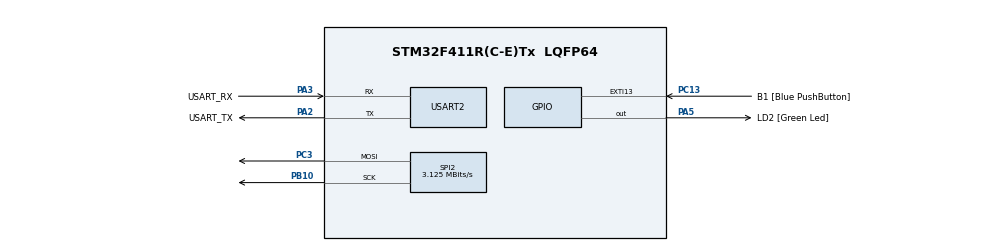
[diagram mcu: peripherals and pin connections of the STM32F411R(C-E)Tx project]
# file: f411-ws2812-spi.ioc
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Dma.Request0=SPI2_TX
Dma.SPI2_TX.0.Direction=DMA_MEMORY_TO_PERIPH
Dma.SPI2_TX.0.FIFOMode=DMA_FIFOMODE_DISABLE
Dma.SPI2_TX.0.Instance=DMA1_Stream4
Dma.SPI2_TX.0.MemDataAlignment=DMA_MDATAALIGN_BYTE
Dma.SPI2_TX.0.MemInc=DMA_MINC_ENABLE
Dma.SPI2_TX.0.Mode=DMA_NORMAL
Dma.SPI2_TX.0.PeriphDataAlignment=DMA_PDATAALIGN_BYTE
Dma.SPI2_TX.0.PeriphInc=DMA_PINC_DISABLE
Dma.SPI2_TX.0.Priority=DMA_PRIORITY_LOW
Mcu.Family=STM32F4
Mcu.Name=STM32F411R(C-E)Tx
Mcu.Package=LQFP64
NVIC.DMA1_Stream4_IRQn=true\:0\:0\:false\:false\:true\:false\:true\:true
NVIC.PriorityGroup=NVIC_PRIORITYGROUP_0
NVIC.SPI2_IRQn=true\:0\:0\:false\:false\:true\:true\:true\:true
PA13.GPIO_Label=TMS
PA13.Mode=Serial_Wire
PA13.Signal=SYS_JTMS-SWDIO
PA14.GPIO_Label=TCK
PA14.Mode=Serial_Wire
PA14.Signal=SYS_JTCK-SWCLK
PA2.GPIO_Label=USART_TX
PA2.Mode=Asynchronous
PA2.Signal=USART2_TX
PA3.GPIO_Label=USART_RX
PA3.Mode=Asynchronous
PA3.Signal=USART2_RX
PA5.GPIO_Label=LD2 [Green Led]
PA5.Signal=GPIO_Output
PB10.Mode=TX_Only_Simplex_Unidirect_Master
PB10.Signal=SPI2_SCK
PB3.GPIO_Label=SWO
PB3.Signal=SYS_JTDO-SWO
PC13-ANTI_TAMP.GPIO_Label=B1 [Blue PushButton]
PC13-ANTI_TAMP.GPIO_ModeDefaultEXTI=GPIO_MODE_IT_FALLING
PC13-ANTI_TAMP.Signal=GPXTI13
PC14-OSC32_IN.Mode=LSE-External-Oscillator
PC14-OSC32_IN.Signal=RCC_OSC32_IN
PC15-OSC32_OUT.Mode=LSE-External-Oscillator
PC15-OSC32_OUT.Signal=RCC_OSC32_OUT
PC3.Mode=TX_Only_Simplex_Unidirect_Master
PC3.Signal=SPI2_MOSI
PH0\ -\ OSC_IN.Mode=HSE-External-Clock-Source
PH0\ -\ OSC_IN.Signal=RCC_OSC_IN
PH1\ -\ OSC_OUT.Mode=HSE-External-Clock-Source
PH1\ -\ OSC_OUT.Signal=RCC_OSC_OUT
ProjectManager.HeapSize=0x200
ProjectManager.StackSize=0x400
ProjectManager.TargetToolchain=STM32CubeIDE
RCC.48MHZClocksFreq_Value=25000000
RCC.AHBFreq_Value=50000000
RCC.APB1CLKDivider=RCC_HCLK_DIV2
RCC.APB1Freq_Value=25000000
RCC.APB1TimFreq_Value=50000000
RCC.APB2Freq_Value=50000000
RCC.APB2TimFreq_Value=50000000
RCC.CortexFreq_Value=50000000
RCC.FLatency-AdvancedSettings=FLASH_LATENCY_1
RCC.HCLKFreq_Value=50000000
RCC.HSE_VALUE=8000000
RCC.HSI_VALUE=16000000
RCC.PLLM=8
RCC.PLLN=50
RCC.SYSCLKFreq_VALUE=50000000
RCC.SYSCLKSource=RCC_SYSCLKSOURCE_PLLCLK
RCC.VCOOutputFreq_Value=100000000
SPI2.BaudRatePrescaler=SPI_BAUDRATEPRESCALER_8
SPI2.CalculateBaudRate=3.125 MBits/s
SPI2.Direction=SPI_DIRECTION_2LINES
SPI2.FirstBit=SPI_FIRSTBIT_MSB
SPI2.Mode=SPI_MODE_MASTER
SPI2.VirtualType=VM_MASTER
USART2.VirtualMode=VM_ASYNC
board=NUCLEO-F411RE

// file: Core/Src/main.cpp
/* USER CODE BEGIN Header */
/**
  ******************************************************************************
  * @file           : main.c
  * @brief          : Main program body
  ******************************************************************************
  * @attention
  *
  * <h2><center>&copy; Copyright (c) 2022 STMicroelectronics.
  * All rights reserved.</center></h2>
  *
  * This software component is licensed by ST under BSD 3-Clause license,
  * the "License"; You may not use this file except in compliance with the
  * License. You may obtain a copy of the License at:
  *                        opensource.org/licenses/BSD-3-Clause
  *
  ******************************************************************************
  */
/* USER CODE END Header */
#include "main.h"

/* USER CODE BEGIN Includes */
#include "stdio.h"
#include "string.h"
#include <functional> // bind

#include "WS2812.h"
#include <RGB.h>
#include <array>

/* USER CODE END Includes */

/* USER CODE BEGIN PD */
#define numleds 60

/* USER CODE END PD */

SPI_HandleTypeDef hspi2;
DMA_HandleTypeDef hdma_spi2_tx;

UART_HandleTypeDef huart2;

/* USER CODE BEGIN PV */

std::array<RGB_t<uint8_t>, 6> rainbow;

//
// USER: change the binding to pass a std::function<void(uint8_t*data, uint32_t length)> to the constructor that writes on the SPI.
// you can use a lambda function as well as std::bind
// examples:
// regular bind
// std::function<void(uint8_t* data, uint32_t length)> spiwrite = std::bind(&HAL_SPI_Transmit, &hspi1, std::placeholders::_1 , std::placeholders::_2, 100);
// lambda function
// std::function<void(uint8_t*data, uint32_t length)> spiwrite = [] (uint8_t* data, uint32_t length) {HAL_SPI_Transmit(&hspi1, data, length, 100);};
 // DMA bind
 std::function<void(uint8_t* data, uint32_t length)> spiwrite = std::bind(&HAL_SPI_Transmit, &hspi2, std::placeholders::_1 , std::placeholders::_2,100);

WS2812<numleds> leds(spiwrite);

const RGB_t<uint8_t>	violet	( 75,   0, 130);
const RGB_t<uint8_t>	blue	  (  0,   0, 255);
const RGB_t<uint8_t>	green	  (  0, 255,   0);
const RGB_t<uint8_t>	yellow	(127, 255,   0);
const RGB_t<uint8_t>	orange	(255,  50,   0);
const RGB_t<uint8_t>	red		  (255,   0,   0);
const RGB_t<uint8_t>	white		  (255,   255,   255);

/* USER CODE END PV */

void SystemClock_Config(void);
static void MX_GPIO_Init(void);
static void MX_USART2_UART_Init(void);
static void MX_DMA_Init(void);
static void MX_SPI2_Init(void);

int main(void)
{
  /* USER CODE BEGIN 1 */
    rainbow[0] = violet;
    rainbow[1] = blue;
    rainbow[2] = green;
    rainbow[3] = yellow;
    rainbow[4] = orange;
    rainbow[5] = red;

  /* USER CODE END 1 */

  /* MCU Configuration--------------------------------------------------------*/

  /* Reset of all peripherals, Initializes the Flash interface and the Systick. */
  HAL_Init();

  /* Configure the system clock */
  SystemClock_Config();

  /* USER CODE BEGIN SysInit */
  MX_DMA_Init();

  /* USER CODE END SysInit */

  /* Initialize all configured peripherals */
  MX_GPIO_Init();
  MX_USART2_UART_Init();
  MX_DMA_Init();
  MX_SPI2_Init();

  /* Infinite loop */
  /* USER CODE BEGIN WHILE */
  while (1)
  {
	  for(int i = 6; i >0 ; i--){

		  for(int j = 0; j < numleds; j++){
			leds.setPixel(j, rainbow[(j+i)%6]);
		  }
		  leds.show();
		  HAL_Delay(50);

		}

    /* USER CODE END WHILE */

  }
}

void SystemClock_Config(void)
{
  RCC_OscInitTypeDef RCC_OscInitStruct = {0};
  RCC_ClkInitTypeDef RCC_ClkInitStruct = {0};

  /** Configure the main internal regulator output voltage
  */
  __HAL_RCC_PWR_CLK_ENABLE();
  __HAL_PWR_VOLTAGESCALING_CONFIG(PWR_REGULATOR_VOLTAGE_SCALE1);
  /** Initializes the RCC Oscillators according to the specified parameters
  * in the RCC_OscInitTypeDef structure.
  */
  RCC_OscInitStruct.OscillatorType = RCC_OSCILLATORTYPE_HSI;
  RCC_OscInitStruct.HSIState = RCC_HSI_ON;
  RCC_OscInitStruct.HSICalibrationValue = RCC_HSICALIBRATION_DEFAULT;
  RCC_OscInitStruct.PLL.PLLState = RCC_PLL_ON;
  RCC_OscInitStruct.PLL.PLLSource = RCC_PLLSOURCE_HSI;
  RCC_OscInitStruct.PLL.PLLM = 8;
  RCC_OscInitStruct.PLL.PLLN = 72;
  RCC_OscInitStruct.PLL.PLLP = RCC_PLLP_DIV2;
  RCC_OscInitStruct.PLL.PLLQ = 4;
  if (HAL_RCC_OscConfig(&RCC_OscInitStruct) != HAL_OK)
  {
    Error_Handler();
  }
  /** Initializes the CPU, AHB and APB buses clocks
  */
  RCC_ClkInitStruct.ClockType = RCC_CLOCKTYPE_HCLK|RCC_CLOCKTYPE_SYSCLK
                              |RCC_CLOCKTYPE_PCLK1|RCC_CLOCKTYPE_PCLK2;
  RCC_ClkInitStruct.SYSCLKSource = RCC_SYSCLKSOURCE_PLLCLK;
  RCC_ClkInitStruct.AHBCLKDivider = RCC_SYSCLK_DIV1;
  RCC_ClkInitStruct.APB1CLKDivider = RCC_HCLK_DIV2;
  RCC_ClkInitStruct.APB2CLKDivider = RCC_HCLK_DIV1;

  if (HAL_RCC_ClockConfig(&RCC_ClkInitStruct, FLASH_LATENCY_2) != HAL_OK)
  {
    Error_Handler();
  }
}

static void MX_SPI2_Init(void)
{

  /* SPI2 parameter configuration*/
  hspi2.Instance = SPI2;
  hspi2.Init.Mode = SPI_MODE_MASTER;
  hspi2.Init.Direction = SPI_DIRECTION_2LINES;
  hspi2.Init.DataSize = SPI_DATASIZE_8BIT;
  hspi2.Init.CLKPolarity = SPI_POLARITY_LOW;
  hspi2.Init.CLKPhase = SPI_PHASE_1EDGE;
  hspi2.Init.NSS = SPI_NSS_SOFT;
  hspi2.Init.BaudRatePrescaler = SPI_BAUDRATEPRESCALER_8;
  hspi2.Init.FirstBit = SPI_FIRSTBIT_MSB;
  hspi2.Init.TIMode = SPI_TIMODE_DISABLE;
  hspi2.Init.CRCCalculation = SPI_CRCCALCULATION_DISABLE;
  hspi2.Init.CRCPolynomial = 10;
  if (HAL_SPI_Init(&hspi2) != HAL_OK)
  {
    Error_Handler();
  }

}

static void MX_USART2_UART_Init(void)
{

  huart2.Instance = USART2;
  huart2.Init.BaudRate = 115200;
  huart2.Init.WordLength = UART_WORDLENGTH_8B;
  huart2.Init.StopBits = UART_STOPBITS_1;
  huart2.Init.Parity = UART_PARITY_NONE;
  huart2.Init.Mode = UART_MODE_TX_RX;
  huart2.Init.HwFlowCtl = UART_HWCONTROL_NONE;
  huart2.Init.OverSampling = UART_OVERSAMPLING_16;
  if (HAL_UART_Init(&huart2) != HAL_OK)
  {
    Error_Handler();
  }

}

static void MX_DMA_Init(void)
{

  /* DMA controller clock enable */
  __HAL_RCC_DMA1_CLK_ENABLE();

  /* DMA interrupt init */
  /* DMA1_Stream4_IRQn interrupt configuration */
  HAL_NVIC_SetPriority(DMA1_Stream4_IRQn, 0, 0);
  HAL_NVIC_EnableIRQ(DMA1_Stream4_IRQn);

}

static void MX_GPIO_Init(void)
{
  GPIO_InitTypeDef GPIO_InitStruct = {0};

  /* GPIO Ports Clock Enable */
  __HAL_RCC_GPIOC_CLK_ENABLE();
  __HAL_RCC_GPIOH_CLK_ENABLE();
  __HAL_RCC_GPIOA_CLK_ENABLE();
  __HAL_RCC_GPIOB_CLK_ENABLE();

  /*Configure GPIO pin Output Level */
  HAL_GPIO_WritePin(LD2_GPIO_Port, LD2_Pin, GPIO_PIN_RESET);

  /*Configure GPIO pin : B1_Pin */
  GPIO_InitStruct.Pin = B1_Pin;
  GPIO_InitStruct.Mode = GPIO_MODE_IT_FALLING;
  GPIO_InitStruct.Pull = GPIO_NOPULL;
  HAL_GPIO_Init(B1_GPIO_Port, &GPIO_InitStruct);

  /*Configure GPIO pin : LD2_Pin */
  GPIO_InitStruct.Pin = LD2_Pin;
  GPIO_InitStruct.Mode = GPIO_MODE_OUTPUT_PP;
  GPIO_InitStruct.Pull = GPIO_NOPULL;
  GPIO_InitStruct.Speed = GPIO_SPEED_FREQ_LOW;
  HAL_GPIO_Init(LD2_GPIO_Port, &GPIO_InitStruct);

}

void Error_Handler(void)
{
  __disable_irq();
  while (1)
  {
  }
}

/************************ (C) COPYRIGHT STMicroelectronics *****END OF FILE****/
